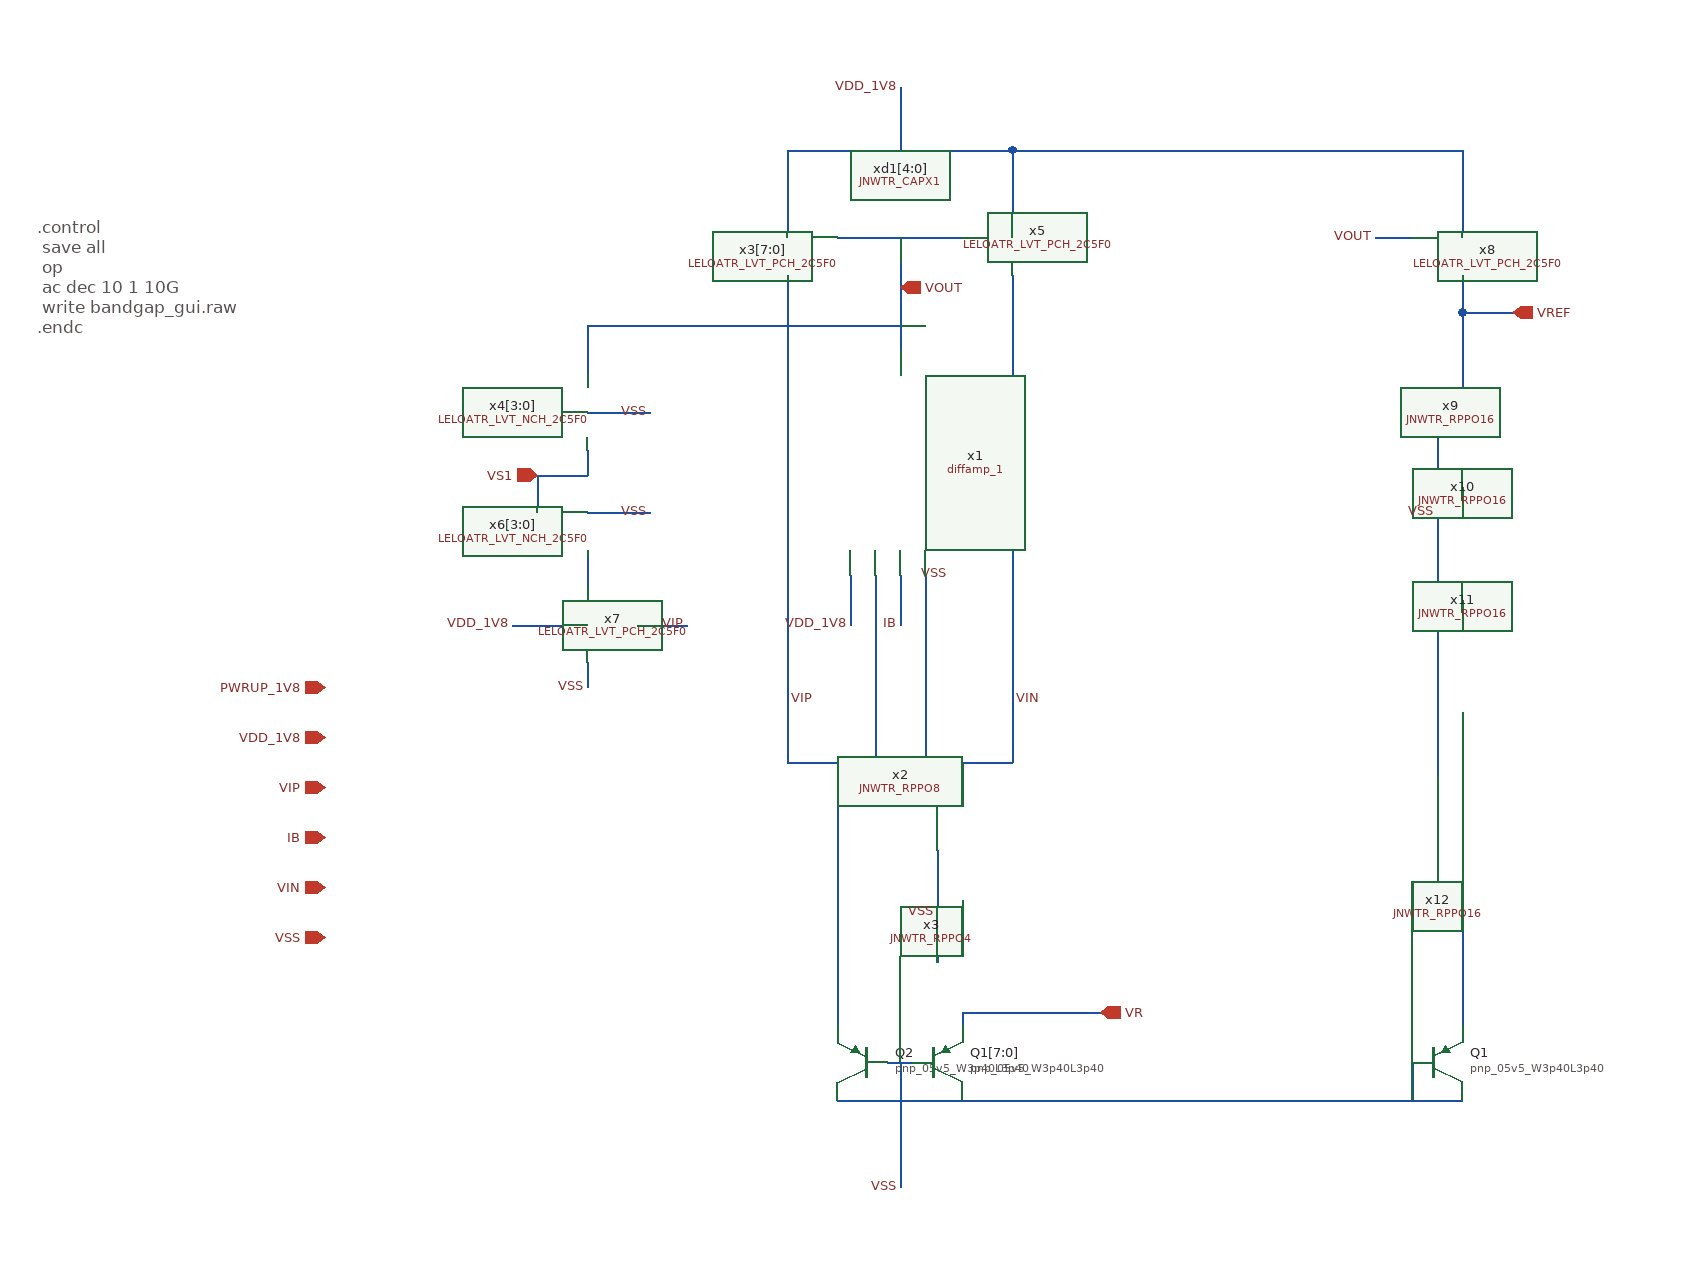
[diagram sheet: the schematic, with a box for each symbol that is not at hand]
v {xschem version=3.4.7 file_version=1.2}
G {}
K {}
V {}
S {}
E {}
B 2 1180 70 1980 470 {flags=graph
y1=-0.15379194
y2=1.846208
ypos1=0
ypos2=2
divy=5
subdivy=1
unity=1
x1=6.552478e-06
x2=6.5524781e-06
divx=5
subdivx=1
xlabmag=1.0
ylabmag=1.0
node="xdut.xd1<4>.xc1.b1
xdut.xd1<4>.xc1.a
xdut.xd1<3>.xc1.b1
xdut.xd1<3>.xc1.a
xdut.xd1<2>.xc1.b1
xdut.xd1<2>.xc1.a
xdut.xd1<1>.xc1.b1
xdut.xd1<1>.xc1.a
xdut.xd1<0>.xc1.b1
xdut.xd1<0>.xc1.a
xdut.x3.xxa1.xr1_7.rb
xdut.x3.xxa1.xr1_6.rb
xdut.x3.xxa1.xr1_5.rb
xdut.x3.xxa1.xr1_4.rb
xdut.x3.xxa1.xr1_3.rb
xdut.x3.xxa1.xr1_2.rb
xdut.x3.xxa1.xr1_1.rb
xdut.x3.xxa1.xr1_0.rb
xdut.x3.xxa1.int_6
xdut.x3.xxa1.int_5
xdut.x3.xxa1.int_4
xdut.x3.xxa1.int_3
xdut.x3.xxa1.int_2
xdut.x3.xxa1.int_1
xdut.x3.xxa1.int_0
xdut.x2.xxa1.xr1_7.rb
xdut.x2.xxa1.xr1_6.rb
xdut.x2.xxa1.xr1_5.rb
xdut.x2.xxa1.xr1_4.rb
xdut.x2.xxa1.xr1_3.rb
xdut.x2.xxa1.xr1_2.rb
xdut.x2.xxa1.xr1_1.rb
xdut.x2.xxa1.xr1_0.rb
xdut.x2.xxa1.int_6
xdut.x2.xxa1.int_5
xdut.x2.xxa1.int_4
xdut.x2.xxa1.int_3
xdut.x2.xxa1.int_2
xdut.x2.xxa1.int_1
xdut.x2.xxa1.int_0
xdut.x1.tail
xdut.x1.net1
xdut.vr
xdut.vout
xdut.net1
vss
vip
vin
vdd_1v8
m.xdut.x5.xm1.msky130_fd_pr__pfet_01v8_lvt#sbody
m.xdut.x5.xm1.msky130_fd_pr__pfet_01v8_lvt#dbody
m.xdut.x5.xm1.msky130_fd_pr__pfet_01v8_lvt#body
m.xdut.x3<7>.xm1.msky130_fd_pr__pfet_01v8_lvt#sbody
m.xdut.x3<7>.xm1.msky130_fd_pr__pfet_01v8_lvt#dbody
m.xdut.x3<7>.xm1.msky130_fd_pr__pfet_01v8_lvt#body
m.xdut.x3<6>.xm1.msky130_fd_pr__pfet_01v8_lvt#sbody
m.xdut.x3<6>.xm1.msky130_fd_pr__pfet_01v8_lvt#dbody
m.xdut.x3<6>.xm1.msky130_fd_pr__pfet_01v8_lvt#body
m.xdut.x3<5>.xm1.msky130_fd_pr__pfet_01v8_lvt#sbody
m.xdut.x3<5>.xm1.msky130_fd_pr__pfet_01v8_lvt#dbody
m.xdut.x3<5>.xm1.msky130_fd_pr__pfet_01v8_lvt#body
m.xdut.x3<4>.xm1.msky130_fd_pr__pfet_01v8_lvt#sbody
m.xdut.x3<4>.xm1.msky130_fd_pr__pfet_01v8_lvt#dbody
m.xdut.x3<4>.xm1.msky130_fd_pr__pfet_01v8_lvt#body
m.xdut.x3<3>.xm1.msky130_fd_pr__pfet_01v8_lvt#sbody
m.xdut.x3<3>.xm1.msky130_fd_pr__pfet_01v8_lvt#dbody
m.xdut.x3<3>.xm1.msky130_fd_pr__pfet_01v8_lvt#body
m.xdut.x3<2>.xm1.msky130_fd_pr__pfet_01v8_lvt#sbody
m.xdut.x3<2>.xm1.msky130_fd_pr__pfet_01v8_lvt#dbody
m.xdut.x3<2>.xm1.msky130_fd_pr__pfet_01v8_lvt#body
m.xdut.x3<1>.xm1.msky130_fd_pr__pfet_01v8_lvt#sbody
m.xdut.x3<1>.xm1.msky130_fd_pr__pfet_01v8_lvt#dbody
m.xdut.x3<1>.xm1.msky130_fd_pr__pfet_01v8_lvt#body
m.xdut.x3<0>.xm1.msky130_fd_pr__pfet_01v8_lvt#sbody
m.xdut.x3<0>.xm1.msky130_fd_pr__pfet_01v8_lvt#dbody
m.xdut.x3<0>.xm1.msky130_fd_pr__pfet_01v8_lvt#body
m.xdut.x1.x6.xm1.msky130_fd_pr__nfet_01v8_lvt#sbody
m.xdut.x1.x6.xm1.msky130_fd_pr__nfet_01v8_lvt#dbody
m.xdut.x1.x6.xm1.msky130_fd_pr__nfet_01v8_lvt#body
m.xdut.x1.x5.xm1.msky130_fd_pr__nfet_01v8_lvt#sbody
m.xdut.x1.x5.xm1.msky130_fd_pr__nfet_01v8_lvt#dbody
m.xdut.x1.x5.xm1.msky130_fd_pr__nfet_01v8_lvt#body
m.xdut.x1.x4.xm1.msky130_fd_pr__pfet_01v8_lvt#sbody
m.xdut.x1.x4.xm1.msky130_fd_pr__pfet_01v8_lvt#dbody
m.xdut.x1.x4.xm1.msky130_fd_pr__pfet_01v8_lvt#body
m.xdut.x1.x3.xm1.msky130_fd_pr__nfet_01v8_lvt#sbody
m.xdut.x1.x3.xm1.msky130_fd_pr__nfet_01v8_lvt#dbody
m.xdut.x1.x3.xm1.msky130_fd_pr__nfet_01v8_lvt#body
m.xdut.x1.x2.xm1.msky130_fd_pr__pfet_01v8_lvt#sbody
m.xdut.x1.x2.xm1.msky130_fd_pr__pfet_01v8_lvt#dbody
m.xdut.x1.x2.xm1.msky130_fd_pr__pfet_01v8_lvt#body
m.xdut.x1.x1.xm1.msky130_fd_pr__nfet_01v8_lvt#sbody
m.xdut.x1.x1.xm1.msky130_fd_pr__nfet_01v8_lvt#dbody
m.xdut.x1.x1.xm1.msky130_fd_pr__nfet_01v8_lvt#body
ib
i(vss)
i(vdd_1v8)"
color="4 4 4 4 4 4 4 4 4 4 4 4 4 4 4 4 4 4 4 4 4 4 4 4 4 4 4 4 4 4 4 4 4 4 4 4 4 4 4 4 4 4 4 4 4 4 4 4 4 4 4 4 4 4 4 4 4 4 4 4 4 4 4 4 4 4 4 4 4 4 4 4 4 4 4 4 4 4 4 4 4 4 4 4 4 4 4 4 4 4 4 4 4 4 4 4 4"
dataset=-1
unitx=1
logx=0
logy=0
rawfile=/home/nikolai/pro/aicex/ip/lelo_gr01_sky130a/sim/bandgap/output_tran/tran_SchGtKttTtVt_op.raw
sim_type=tran}
P 4 1 60 -60 {}
P 4 1 -130 -150 {}
P 4 1 -80 420 {}
P 4 1 -290 700 {}
T {.control
  save all
  op
  ac dec 10 1 10G
  write bandgap_gui.raw
.endc} -690 -20 0 0 0.4 0.4 {}
N 0 0 0 90 {lab=VOUT}
N -50 420 -50 630 {lab=VIP}
N -90 30 -90 420 {lab=VIP}
N -90 -30 -90 0 {lab=VDD_1V8}
N 0 -120 0 -100 {lab=VDD_1V8}
N -90 -50 -90 -30 {lab=VDD_1V8}
N -40 270 -40 310 {lab=VDD_1V8}
N -90 420 -20 420 {lab=VIP}
N -0 270 -0 310 {lab=IB}
N 0 730 0 760 {lab=VSS}
N -50 0 50 0 {lab=VOUT}
N 90 -50 90 -30 {lab=VDD_1V8}
N -90 -70 90 -70 {lab=VDD_1V8}
N 90 -70 90 -50 {lab=VDD_1V8}
N -90 -70 -90 -50 {lab=VDD_1V8}
N -0 -100 -0 -70 {lab=VDD_1V8}
N -0 660 -0 730 {lab=VSS}
N -50 690 -0 690 {lab=VSS}
N -0 690 50 690 {lab=VSS}
N 50 420 50 450 {lab=VIN}
N 20 420 90 420 {lab=VIN}
N 30 490 30 580 {lab=VSS}
N 50 530 50 540 {lab=#net1}
N 90 -30 90 -0 {lab=VDD_1V8}
N -250 70 -250 110 {lab=VOUT}
N -250 70 0 70 {lab=VOUT}
N -250 140 -200 140 {lab=VSS}
N -250 220 -200 220 {lab=VSS}
N -250 170 -250 190 {lab=VS1}
N -290 190 -250 190 {lab=VS1}
N -290 190 -290 220 {lab=VS1}
N -210 310 -170 310 {lab=VIP}
N -310 310 -250 310 {lab=VDD_1V8}
N -250 250 -250 280 {lab=#net2}
N -250 340 -250 360 {lab=VSS}
N -10 660 10 660 {lab=VSS}
N -20 270 -20 330 {lab=VIP}
N 20 270 20 330 {lab=VIN}
N 50 620 50 630 {lab=VR}
N 90 -70 250 -70 {lab=VDD_1V8}
N 450 -30 450 0 {lab=VDD_1V8}
N 380 0 410 0 {lab=VOUT}
N 450 30 450 60 {lab=VREF}
N 450 60 490 60 {lab=VREF}
N 50 620 160 620 {lab=VR}
N 450 60 450 120 {lab=VREF}
N 450 200 450 210 {lab=#net3}
N 450 290 450 300 {lab=#net4}
N 50 690 250 690 {lab=VSS}
N 410 660 410 690 {lab=VSS}
N 430 160 430 340 {lab=VSS}
N 450 470 450 630 {lab=#net5}
N 450 380 450 390 {lab=#net6}
N 430 340 430 430 {lab=VSS}
N -20 330 -20 420 {lab=VIP}
N 20 330 20 420 {lab=VIN}
N 90 30 90 70 {lab=VIN}
N 90 70 90 100 {lab=VIN}
N 90 130 90 370 {lab=VIN}
N 90 370 90 420 {lab=VIN}
N 250 -70 440 -70 {lab=VDD_1V8}
N 250 690 450 690 {lab=VSS}
N 450 -70 450 -30 {lab=VDD_1V8}
N 440 -70 450 -70 {lab=VDD_1V8}
N 90 100 90 130 {lab=VIN}
C {devices/lab_wire.sym} -40 310 0 0 {name=p2 sig_type=std_logic lab=VDD_1V8}
C {devices/lab_wire.sym} 0 310 0 0 {name=p4 sig_type=std_logic lab=IB}
C {devices/lab_wire.sym} 40 270 3 0 {name=p6 sig_type=std_logic lab=VSS}
C {devices/ipin.sym} -460 400 0 0 {name=p7 lab=VDD_1V8}
C {devices/ipin.sym} -460 440 0 0 {name=p8 lab=VIP}
C {devices/ipin.sym} -460 480 0 0 {name=p9 lab=IB}
C {devices/ipin.sym} -460 520 0 0 {name=p10 lab=VIN}
C {devices/ipin.sym} -460 560 0 0 {name=p11 lab=VSS}
C {devices/lab_wire.sym} 0 -120 0 0 {name=p1 sig_type=std_logic lab=VDD_1V8}
C {devices/lab_wire.sym} 0 760 0 0 {name=p12 sig_type=std_logic lab=VSS}
C {LELO_ATR_SKY130A/LELOATR_LVT_PCH_2C5F0.sym} 50 0 0 0 {name=x5}
C {LELO_ATR_SKY130A/LELOATR_LVT_PCH_2C5F0.sym} -50 0 0 1 {name=x3[7:0]}
C {JNW_TR_SKY130A/JNWTR_CAPX1.sym} 0 -60 2 1 {name=xd1[4:0]}
C {sky130_fd_pr/pnp_05v5.sym} -30 660 0 1 {name=Q2
model=pnp_05v5_W3p40L3p40
m=1
spiceprefix=X
}
C {sky130_fd_pr/pnp_05v5.sym} 30 660 0 0 {name=Q1[7:0]
model=pnp_05v5_W3p40L3p40
m=1
spiceprefix=X
}
C {LELO_GR01_SKY130A/diffamp_1.sym} 0 120 3 0 {name=x1}
C {devices/lab_wire.sym} 90 370 2 0 {name=p3 sig_type=std_logic lab=VIN}
C {devices/lab_wire.sym} -90 370 2 0 {name=p5 sig_type=std_logic lab=VIP
}
C {JNW_TR_SKY130A/JNWTR_RPPO8.sym} 50 450 1 0 {name=x2 }
C {JNW_TR_SKY130A/JNWTR_RPPO4.sym} 50 540 1 0 {name=x3 }
C {devices/lab_wire.sym} 30 540 0 0 {name=p14 sig_type=std_logic lab=VSS}
C {LELO_ATR_SKY130A/LELOATR_LVT_NCH_2C5F0.sym} -290 140 0 0 {name=x4[3:0]}
C {LELO_ATR_SKY130A/LELOATR_LVT_NCH_2C5F0.sym} -290 220 0 0 {name=x6[3:0]}
C {devices/ipin.sym} -460 360 0 0 {name=p15 lab=PWRUP_1V8}
C {devices/lab_wire.sym} -200 140 0 0 {name=p17 sig_type=std_logic lab=VSS}
C {devices/lab_wire.sym} -200 220 0 0 {name=p18 sig_type=std_logic lab=VSS}
C {LELO_ATR_SKY130A/LELOATR_LVT_PCH_2C5F0.sym} -210 310 0 1 {name=x7}
C {devices/lab_wire.sym} -170 310 0 0 {name=p19 sig_type=std_logic lab=VIP
}
C {devices/lab_wire.sym} -310 310 0 0 {name=p20 sig_type=std_logic lab=VDD_1V8}
C {devices/lab_wire.sym} -250 360 0 0 {name=p21 sig_type=std_logic lab=VSS}
C {devices/ipin.sym} -290 190 0 0 {name=p22 lab=VS1}
C {devices/opin.sym} 0 40 0 0 {name=p23 lab=VOUT}
C {devices/opin.sym} 160 620 0 0 {name=p13 lab=VR}
C {LELO_ATR_SKY130A/LELOATR_LVT_PCH_2C5F0.sym} 410 0 0 0 {name=x8}
C {devices/lab_wire.sym} 380 0 0 0 {name=p16 sig_type=std_logic lab=VOUT}
C {devices/opin.sym} 490 60 0 0 {name=p24 lab=VREF}
C {JNW_TR_SKY130A/JNWTR_RPPO16.sym} 450 120 1 0 {name=x9}
C {JNW_TR_SKY130A/JNWTR_RPPO16.sym} 450 210 1 0 {name=x10 }
C {JNW_TR_SKY130A/JNWTR_RPPO16.sym} 450 300 1 0 {name=x11 }
C {sky130_fd_pr/pnp_05v5.sym} 430 660 0 0 {name=Q1
model=pnp_05v5_W3p40L3p40
m=1
spiceprefix=X
}
C {devices/lab_wire.sym} 430 220 0 0 {name=p25 sig_type=std_logic lab=VSS}
C {JNW_TR_SKY130A/JNWTR_RPPO16.sym} 450 390 1 0 {name=x12 }
